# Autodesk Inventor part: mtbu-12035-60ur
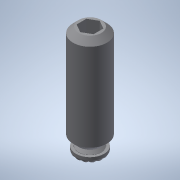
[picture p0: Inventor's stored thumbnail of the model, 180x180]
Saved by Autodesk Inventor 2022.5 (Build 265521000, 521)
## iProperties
Created: 2017-08
Part Number: mtbu-12035-60ur
Material: 一般
Document SubType Name: Modeling
Designer: imaocorp
Density: 1 g/cm^3
Appearance: 既定
Author: imaocorp
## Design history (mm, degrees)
node "mtbu-12035-60ur.x_t1"
node "mtbu-12035-60ur"
node "Base1"
